One B-rep face of a CAD part: STEP entity #1190.
In plain terms, the planar face has unit normal (1, 0, 0).
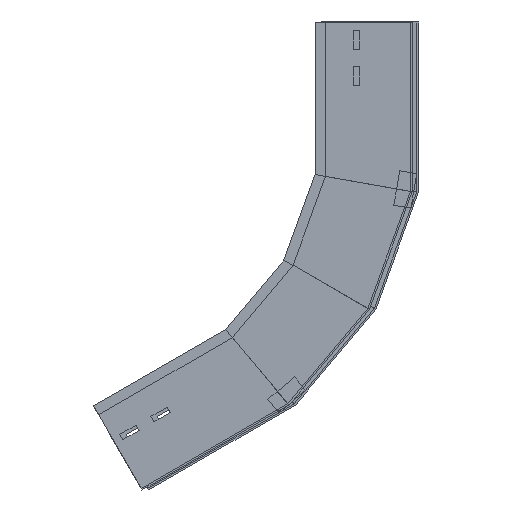
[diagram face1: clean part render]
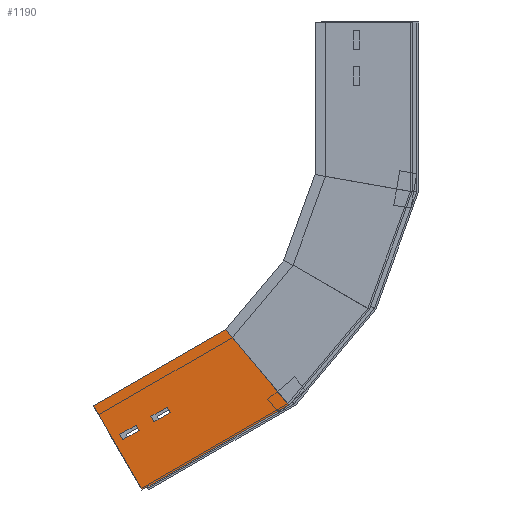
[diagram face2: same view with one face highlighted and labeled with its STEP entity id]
Its self-contained STEP definition (entity closure, numbers rounded to 3 decimals):
#3 = VECTOR ( 'NONE', #500, 1000. ) ;
#33 = VECTOR ( 'NONE', #753, 1000. ) ;
#45 = VERTEX_POINT ( 'NONE', #1086 ) ;
#58 = EDGE_CURVE ( 'NONE', #917, #501, #122, .T. ) ;
#67 = ORIENTED_EDGE ( 'NONE', *, *, #960, .F. ) ;
#85 = EDGE_CURVE ( 'NONE', #1365, #917, #519, .T. ) ;
#90 = LINE ( 'NONE', #238, #33 ) ;
#99 = DIRECTION ( 'NONE',  ( 0., 0., 1. ) ) ;
#119 = VERTEX_POINT ( 'NONE', #149 ) ;
#122 = LINE ( 'NONE', #417, #819 ) ;
#143 = VECTOR ( 'NONE', #545, 1000. ) ;
#149 = CARTESIAN_POINT ( 'NONE',  ( 0., 0., -196.6 ) ) ;
#180 = EDGE_CURVE ( 'NONE', #45, #1408, #1325, .T. ) ;
#189 = VECTOR ( 'NONE', #237, 1000. ) ;
#202 = ORIENTED_EDGE ( 'NONE', *, *, #180, .T. ) ;
#211 = VERTEX_POINT ( 'NONE', #901 ) ;
#212 = CARTESIAN_POINT ( 'NONE',  ( 0., 61.5, -73.505 ) ) ;
#220 = DIRECTION ( 'NONE',  ( 0., -0.985, -0.174 ) ) ;
#233 = EDGE_CURVE ( 'NONE', #1395, #119, #439, .T. ) ;
#237 = DIRECTION ( 'NONE',  ( 0., 1., 0. ) ) ;
#238 = CARTESIAN_POINT ( 'NONE',  ( 0., 68.5, -73.505 ) ) ;
#306 = LINE ( 'NONE', #584, #815 ) ;
#353 = VERTEX_POINT ( 'NONE', #752 ) ;
#357 = CARTESIAN_POINT ( 'NONE',  ( 0., 0., 0. ) ) ;
#361 = ORIENTED_EDGE ( 'NONE', *, *, #642, .T. ) ;
#362 = VERTEX_POINT ( 'NONE', #212 ) ;
#364 = LINE ( 'NONE', #1145, #3 ) ;
#370 = EDGE_CURVE ( 'NONE', #501, #444, #499, .T. ) ;
#380 = EDGE_CURVE ( 'NONE', #869, #119, #864, .T. ) ;
#386 = ORIENTED_EDGE ( 'NONE', *, *, #233, .T. ) ;
#417 = CARTESIAN_POINT ( 'NONE',  ( 0., 61.5, -9.835 ) ) ;
#439 = LINE ( 'NONE', #946, #1362 ) ;
#444 = VERTEX_POINT ( 'NONE', #1264 ) ;
#496 = CARTESIAN_POINT ( 'NONE',  ( 0., 68.5, -9.835 ) ) ;
#499 = LINE ( 'NONE', #1643, #189 ) ;
#500 = DIRECTION ( 'NONE',  ( 0., 0., -1. ) ) ;
#501 = VERTEX_POINT ( 'NONE', #516 ) ;
#516 = CARTESIAN_POINT ( 'NONE',  ( 0., 61.5, -9.835 ) ) ;
#519 = LINE ( 'NONE', #640, #763 ) ;
#520 = VECTOR ( 'NONE', #631, 1000. ) ;
#526 = CARTESIAN_POINT ( 'NONE',  ( 0., 0., 0. ) ) ;
#541 = ORIENTED_EDGE ( 'NONE', *, *, #1146, .T. ) ;
#545 = DIRECTION ( 'NONE',  ( 0., 1., 0. ) ) ;
#569 = VECTOR ( 'NONE', #220, 1000. ) ;
#575 = EDGE_CURVE ( 'NONE', #353, #869, #795, .T. ) ;
#584 = CARTESIAN_POINT ( 'NONE',  ( 0., 61.5, -51.505 ) ) ;
#595 = FACE_BOUND ( 'NONE', #619, .T. ) ;
#599 = ORIENTED_EDGE ( 'NONE', *, *, #1633, .T. ) ;
#619 = EDGE_LOOP ( 'NONE', ( #202, #1120, #541, #361 ) ) ;
#631 = DIRECTION ( 'NONE',  ( 0., 1., 0. ) ) ;
#640 = CARTESIAN_POINT ( 'NONE',  ( 0., 68.5, -31.835 ) ) ;
#642 = EDGE_CURVE ( 'NONE', #362, #45, #306, .T. ) ;
#686 = ORIENTED_EDGE ( 'NONE', *, *, #58, .T. ) ;
#715 = VECTOR ( 'NONE', #1276, 1000. ) ;
#744 = FACE_OUTER_BOUND ( 'NONE', #1436, .T. ) ;
#752 = CARTESIAN_POINT ( 'NONE',  ( 0., 112.5, 0. ) ) ;
#753 = DIRECTION ( 'NONE',  ( 0., -1., 0. ) ) ;
#763 = VECTOR ( 'NONE', #1425, 1000. ) ;
#790 = LINE ( 'NONE', #1443, #143 ) ;
#795 = LINE ( 'NONE', #1039, #1166 ) ;
#815 = VECTOR ( 'NONE', #1202, 1000. ) ;
#819 = VECTOR ( 'NONE', #1551, 1000. ) ;
#848 = DIRECTION ( 'NONE',  ( 0., 0., -1. ) ) ;
#864 = LINE ( 'NONE', #1381, #569 ) ;
#869 = VERTEX_POINT ( 'NONE', #1525 ) ;
#901 = CARTESIAN_POINT ( 'NONE',  ( 0., 68.5, -73.505 ) ) ;
#902 = CARTESIAN_POINT ( 'NONE',  ( 0., 61.5, -31.835 ) ) ;
#917 = VERTEX_POINT ( 'NONE', #902 ) ;
#946 = CARTESIAN_POINT ( 'NONE',  ( 0., 0., 0. ) ) ;
#960 = EDGE_CURVE ( 'NONE', #1395, #353, #790, .T. ) ;
#1008 = PLANE ( 'NONE',  #1321 ) ;
#1012 = ORIENTED_EDGE ( 'NONE', *, *, #370, .T. ) ;
#1039 = CARTESIAN_POINT ( 'NONE',  ( 0., 112.5, 0. ) ) ;
#1086 = CARTESIAN_POINT ( 'NONE',  ( 0., 61.5, -51.505 ) ) ;
#1111 = FACE_BOUND ( 'NONE', #1270, .T. ) ;
#1120 = ORIENTED_EDGE ( 'NONE', *, *, #1250, .T. ) ;
#1145 = CARTESIAN_POINT ( 'NONE',  ( 0., 68.5, -51.505 ) ) ;
#1146 = EDGE_CURVE ( 'NONE', #211, #362, #90, .T. ) ;
#1162 = CARTESIAN_POINT ( 'NONE',  ( 0., 68.5, -51.505 ) ) ;
#1166 = VECTOR ( 'NONE', #1557, 1000. ) ;
#1190 = ADVANCED_FACE ( 'NONE', ( #595, #744, #1111 ), #1008, .F. ) ;
#1202 = DIRECTION ( 'NONE',  ( 0., 0., 1. ) ) ;
#1250 = EDGE_CURVE ( 'NONE', #1408, #211, #364, .T. ) ;
#1264 = CARTESIAN_POINT ( 'NONE',  ( 0., 68.5, -9.835 ) ) ;
#1270 = EDGE_LOOP ( 'NONE', ( #1012, #599, #1642, #686 ) ) ;
#1276 = DIRECTION ( 'NONE',  ( 0., 0., -1. ) ) ;
#1321 = AXIS2_PLACEMENT_3D ( 'NONE', #357, #1645, #99 ) ;
#1325 = LINE ( 'NONE', #1432, #520 ) ;
#1327 = ORIENTED_EDGE ( 'NONE', *, *, #380, .F. ) ;
#1362 = VECTOR ( 'NONE', #848, 1000. ) ;
#1365 = VERTEX_POINT ( 'NONE', #1676 ) ;
#1381 = CARTESIAN_POINT ( 'NONE',  ( 0., 33.621, -190.672 ) ) ;
#1395 = VERTEX_POINT ( 'NONE', #526 ) ;
#1408 = VERTEX_POINT ( 'NONE', #1162 ) ;
#1425 = DIRECTION ( 'NONE',  ( 0., -1., 0. ) ) ;
#1432 = CARTESIAN_POINT ( 'NONE',  ( 0., 68.5, -51.505 ) ) ;
#1436 = EDGE_LOOP ( 'NONE', ( #1495, #67, #386, #1327 ) ) ;
#1443 = CARTESIAN_POINT ( 'NONE',  ( 0., 0., 0. ) ) ;
#1495 = ORIENTED_EDGE ( 'NONE', *, *, #575, .F. ) ;
#1525 = CARTESIAN_POINT ( 'NONE',  ( 0., 112.5, -176.763 ) ) ;
#1551 = DIRECTION ( 'NONE',  ( 0., 0., 1. ) ) ;
#1557 = DIRECTION ( 'NONE',  ( 0., 0., -1. ) ) ;
#1633 = EDGE_CURVE ( 'NONE', #444, #1365, #1638, .T. ) ;
#1638 = LINE ( 'NONE', #496, #715 ) ;
#1642 = ORIENTED_EDGE ( 'NONE', *, *, #85, .T. ) ;
#1643 = CARTESIAN_POINT ( 'NONE',  ( 0., 68.5, -9.835 ) ) ;
#1645 = DIRECTION ( 'NONE',  ( -1., 0., 0. ) ) ;
#1676 = CARTESIAN_POINT ( 'NONE',  ( 0., 68.5, -31.835 ) ) ;
